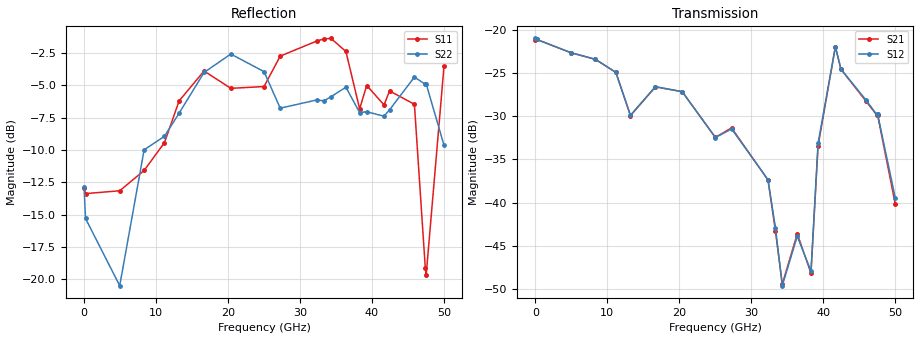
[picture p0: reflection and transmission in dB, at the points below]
!Keysight Technologies,N5245B,MY58422270,A.16.20.02
!Date: Thursday, March 05, 2026 01:24:34
!Correction: S11(C  2-Port  )
!S21(C  2-Port  )
!S12(C  2-Port  )
!S22(C  2-Port  )
!S2P File: Measurements: S11, S21, S12, S22:
# Hz S  dB  R 50
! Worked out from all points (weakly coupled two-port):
!   3201 points, 10 MHz to 50 GHz, reference 50 ohm
!   highest |S21| = -21.13 dB at 213.1 MHz (marker M1); lowest = -49.4 dB at 34.3 GHz (marker M2)
!   lowest |S11| = -19.6 dB at 47.53 GHz (marker M3), VSWR 1.23, Z = 45.9 + j9.18 ohm
!   |S11| at or under -10 dB: start of sweep to 10.12 GHz; 11.36 GHz to 11.92 GHz (562.6 MHz wide, 4.83 % of centre); 46.66 GHz to 48.28 GHz (1.623 GHz wide, 3.42 % of centre)
!   |S22| runs from -20.5 to -2.5 dB; largest |S21 - S12| = 0.0045
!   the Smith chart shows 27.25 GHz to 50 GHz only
!   S11 on the Smith chart (normalised r, x): 27.25 GHz: 0.18, +0.37; 32.32 GHz: 0.42, +1.87; 36.38 GHz: 2.36, -3.32; 42.44 GHz: 1.00, -1.27; 47.41 GHz: 0.84, +0.13; 50 GHz: 0.62, -1.35
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1e7  -12.93 -3.6  -21.19 2.1  -21.00 4.7  -12.89 33.5
2.130844e8  -13.37 -9.5  -21.13 -7.3  -21.13 -7.0  -15.29 -0.4
4.962134e9  -13.15 -123.3  -22.67 167.0  -22.66 166.9  -20.48 -128.2
8.352081e9  -11.58 174.8  -23.44 25.9  -23.42 25.8  -9.99 -160.0
1.117964e10  -9.43 105.8  -24.93 -84.1  -24.94 -84.4  -8.94 89.4
1.321048e10  -6.21 62.7  -29.94 -142.3  -29.90 -142.7  -7.16 -20.9
1.667854e10  -3.90 -43.8  -26.61 157.8  -26.59 157.9  -4.01 -139.5
2.039655e10  -5.24 -121.5  -27.17 40.2  -27.17 39.6  -2.59 155.5
2.5005e10  -5.10 179.7  -32.45 -64.6  -32.48 -64.9  -3.95 71.4
2.725455e10  -2.75 138.3  -31.36 -115.0  -31.48 -113.8  -6.77 31.1
3.231604e10  -1.59 54.5  -37.39 47.7  -37.36 49.2  -6.14 -103.8
3.334708e10  -1.42 36.1  -43.27 2.1  -42.93 -1.6  -6.20 -126.2
3.430002e10  -1.38 19.1  -49.44 -85.5  -49.62 -99.4  -5.89 -146.2
3.637772e10  -2.39 -23.0  -43.61 110.7  -43.89 110.5  -5.15 174.2
3.828359e10  -6.82 -22.2  -48.18 87.5  -47.95 85.4  -7.11 139.1
3.926777e10  -5.02 -33.5  -33.44 88.8  -33.13 88.8  -7.05 137.0
4.167354e10  -6.52 -52.5  -21.96 -58.8  -21.97 -58.7  -7.39 117.6
4.243901e10  -5.44 -57.6  -24.56 -119.5  -24.56 -119.3  -6.90 113.3
4.589145e10  -6.47 -117.4  -28.23 55.0  -28.10 54.7  -4.37 63.3
4.740677e10  -19.12 137.4  -29.87 -2.3  -29.81 -2.8  -4.93 42.8
4.753174e10  -19.62 108.6  -29.85 -4.1  -29.75 -5.5  -4.90 41.3
5e10  -3.55 -66.0  -40.20 -149.8  -39.48 -149.7  -9.63 2.7
